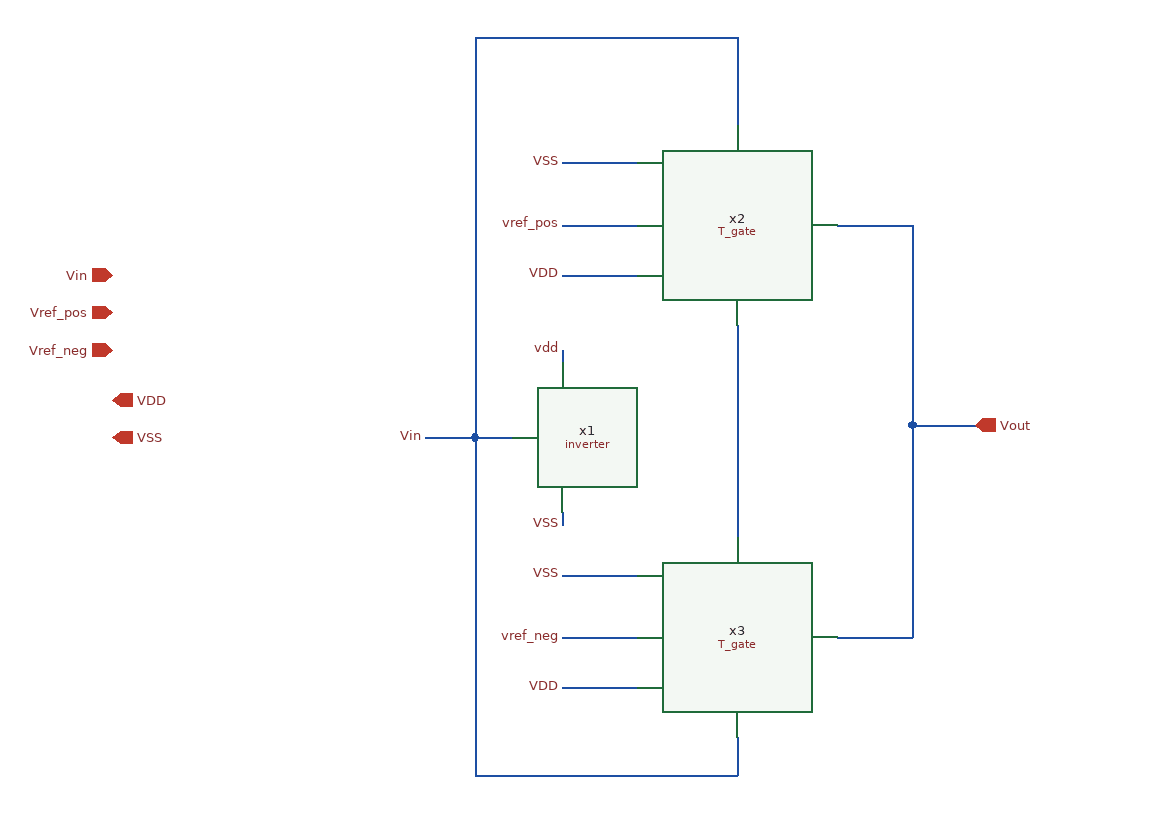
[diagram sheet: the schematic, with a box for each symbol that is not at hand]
v {xschem version=3.4.6 file_version=1.2}
G {}
K {}
V {}
S {}
E {}
N 390 -50 390 -20 {lab=Vin}
N 470 -130 530 -130 {lab=Vout}
N 390 -380 390 -210 {lab=#net1}
N 470 -460 530 -460 {lab=Vout}
N 530 -300 530 -130 {lab=Vout}
N 530 -460 530 -300 {lab=Vout}
N 390 -610 390 -540 {lab=Vin}
N 180 -610 390 -610 {lab=Vin}
N 180 -610 180 -290 {lab=Vin}
N 180 -290 210 -290 {lab=Vin}
N 250 -130 310 -130 {lab=vref_neg}
N 250 -90 310 -90 {lab=VDD}
N 250 -180 310 -180 {lab=VSS}
N 180 -290 180 -20 {lab=Vin}
N 180 -20 390 -20 {lab=Vin}
N 250 -460 310 -460 {lab=vref_pos}
N 250 -420 310 -420 {lab=VDD}
N 250 -510 310 -510 {lab=VSS}
N 140 -290 180 -290 {lab=Vin}
N 250 -360 250 -350 {lab=vdd}
N 250 -230 250 -220 {lab=#net2}
N 530 -300 580 -300 {lab=Vout}
C {lab_pin.sym} 250 -90 0 0 {name=p6 sig_type=std_logic lab=VDD}
C {lab_pin.sym} 250 -420 0 0 {name=p7 sig_type=std_logic lab=VDD}
C {lab_pin.sym} 250 -460 0 0 {name=p8 sig_type=std_logic lab=vref_pos}
C {lab_pin.sym} 140 -290 0 0 {name=p9 sig_type=std_logic lab=Vin}
C {lab_pin.sym} 250 -360 0 0 {name=p4 sig_type=std_logic lab=vdd}
C {/home/designer/shared/IHP-AnalogAcademy/modules/module_3_8_bit_SAR_ADC/part_2_digital_comps/T_gate/schematic/T_gate.sym} 390 -460 2 1 {name=x2}
C {/home/designer/shared/IHP-AnalogAcademy/modules/module_3_8_bit_SAR_ADC/part_2_digital_comps/T_gate/schematic/T_gate.sym} 390 -130 2 1 {name=x3}
C {/home/designer/shared/IHP-AnalogAcademy/modules/module_3_8_bit_SAR_ADC/part_2_digital_comps/bootstrap_switch/schematic/inverter.sym} 230 -290 0 0 {name=x1}
C {lab_pin.sym} 250 -130 0 0 {name=p10 sig_type=std_logic lab=vref_neg}
C {ipin.sym} -110 -420 0 0 {name=p1 lab=Vin}
C {ipin.sym} -110 -390 0 0 {name=p2 lab=Vref_pos}
C {ipin.sym} -110 -360 0 0 {name=p3 lab=Vref_neg}
C {iopin.sym} -110 -320 0 1 {name=p11 lab=VDD}
C {iopin.sym} -110 -290 0 1 {name=p12 lab=VSS}
C {lab_pin.sym} 250 -510 0 0 {name=p13 sig_type=std_logic lab=VSS}
C {lab_pin.sym} 250 -180 0 0 {name=p14 sig_type=std_logic lab=VSS}
C {opin.sym} 580 -300 0 0 {name=p15 lab=Vout}
C {lab_pin.sym} 250 -220 0 0 {name=p5 sig_type=std_logic lab=VSS}
